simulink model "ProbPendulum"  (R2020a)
settings: Solver=ode45  StartTime=0.0  StopTime=10.0  MaxStep=0.01  RelTol=1e-3  EnableMultiTasking=on
PreLoadFcn:
  | %% 単振子の運動解析
  | deg2rad = pi/180;
  | g = 9.8;    % [m/s^2]
  | L = 1;      % [m]
  | 
  | omega = sqrt(g/L);
  | th0 = 40;
  | %th0 = 40*deg2rad;% [rad]　最大角度
  | %k = sin(th0/2);

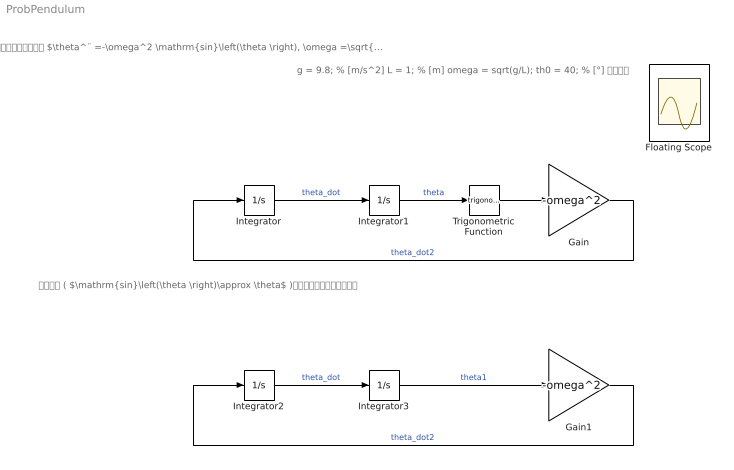
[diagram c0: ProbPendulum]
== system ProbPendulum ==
  note: 線形近似 ( $\mathrm{sin}\left(\theta \right)\approx \theta$ )で解いた場合と比較せよ。
  note: g = 9.8; % [m/s^2] L = 1; % [m] omega = sqrt(g/L); th0 = 40; % [°] 初期角度
  note: 単振子の微分方程式 $\theta^¨ =-\omega^2 \mathrm{sin}\left(\theta \right), \omega =\sqrt{\frac{g}{l}}$ , をブロック線図を用いて解け
  Floating Scope : Scope
  Gain : Gain  Gain=-omega^2
  Gain1 : Gain  Gain=-omega^2
  Integrator : Integrator
  Integrator1 : Integrator  InitialCondition=th0/180*pi
  Integrator2 : Integrator
  Integrator3 : Integrator  InitialCondition=th0/180*pi
  Trigonometric Function : Trigonometry
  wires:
  Integrator/1 -> Integrator1/1  "theta_dot"
  Integrator1/1 -> Trigonometric Function/1  "theta"
  Trigonometric Function/1 -> Gain/1
  Gain/1 -> Integrator/1  "theta_dot2"
  Integrator3/1 -> Gain1/1  "theta1"
  Integrator2/1 -> Integrator3/1  "theta_dot"
  Gain1/1 -> Integrator2/1  "theta_dot2"
